One B-rep face of a CAD part: STEP entity #1113.
In plain terms, the planar face has unit normal (-1, 0, 0).
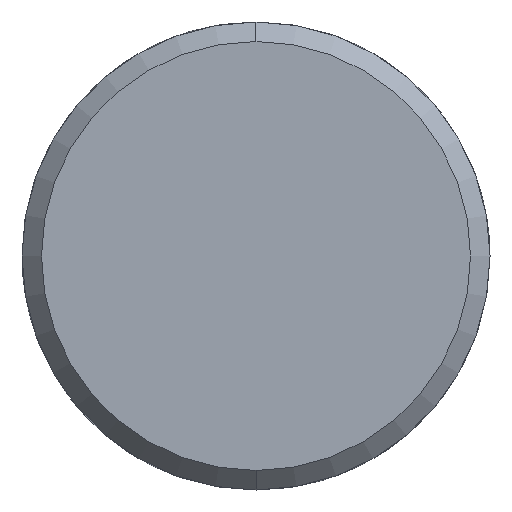
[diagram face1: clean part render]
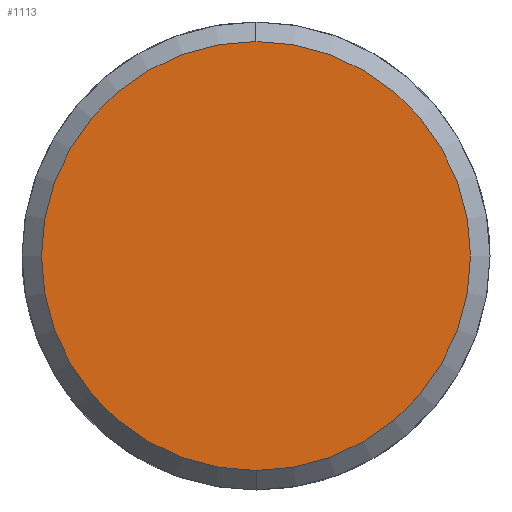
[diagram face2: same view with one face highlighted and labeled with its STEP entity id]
Its self-contained STEP definition (entity closure, numbers rounded to 3 decimals):
#1045=CARTESIAN_POINT('Vertex',(-5.,0.,-11.)) ;
#1048=CARTESIAN_POINT('Axis2P3D Location',(-5.,0.,0.)) ;
#1052=CARTESIAN_POINT('Vertex',(-5.,11.,0.)) ;
#1055=CARTESIAN_POINT('Axis2P3D Location',(-5.,0.,0.)) ;
#1059=CARTESIAN_POINT('Vertex',(-5.,0.,11.)) ;
#1081=CARTESIAN_POINT('Axis2P3D Location',(-5.,0.,0.)) ;
#1085=CARTESIAN_POINT('Vertex',(-5.,-11.,0.)) ;
#1088=CARTESIAN_POINT('Axis2P3D Location',(-5.,0.,0.)) ;
#1102=CARTESIAN_POINT('Axis2P3D Location',(-5.,0.,0.)) ;
#1049=DIRECTION('Axis2P3D Direction',(1.,0.,-0.)) ;
#1056=DIRECTION('Axis2P3D Direction',(1.,0.,-0.)) ;
#1082=DIRECTION('Axis2P3D Direction',(1.,0.,-0.)) ;
#1089=DIRECTION('Axis2P3D Direction',(1.,0.,-0.)) ;
#1103=DIRECTION('Axis2P3D Direction',(1.,0.,-0.)) ;
#1104=DIRECTION('Axis2P3D XDirection',(-0.,0.,-1.)) ;
#1050=AXIS2_PLACEMENT_3D('Circle Axis2P3D',#1048,#1049,$) ;
#1057=AXIS2_PLACEMENT_3D('Circle Axis2P3D',#1055,#1056,$) ;
#1083=AXIS2_PLACEMENT_3D('Circle Axis2P3D',#1081,#1082,$) ;
#1090=AXIS2_PLACEMENT_3D('Circle Axis2P3D',#1088,#1089,$) ;
#1105=AXIS2_PLACEMENT_3D('Plane Axis2P3D',#1102,#1103,#1104) ;
#1108=ORIENTED_EDGE('',*,*,#1054,.F.) ;
#1109=ORIENTED_EDGE('',*,*,#1092,.F.) ;
#1110=ORIENTED_EDGE('',*,*,#1087,.F.) ;
#1111=ORIENTED_EDGE('',*,*,#1061,.F.) ;
#1113=ADVANCED_FACE('351-14X46X70',(#1112),#1106,.F.) ;
#1051=CIRCLE('generated circle',#1050,11.) ;
#1058=CIRCLE('generated circle',#1057,11.) ;
#1084=CIRCLE('generated circle',#1083,11.) ;
#1091=CIRCLE('generated circle',#1090,11.) ;
#1054=EDGE_CURVE('',#1046,#1053,#1051,.T.) ;
#1061=EDGE_CURVE('',#1053,#1060,#1058,.T.) ;
#1087=EDGE_CURVE('',#1060,#1086,#1084,.T.) ;
#1092=EDGE_CURVE('',#1086,#1046,#1091,.T.) ;
#1107=EDGE_LOOP('',(#1108,#1109,#1110,#1111)) ;
#1112=FACE_OUTER_BOUND('',#1107,.T.) ;
#1106=PLANE('Plane',#1105) ;
#1046=VERTEX_POINT('',#1045) ;
#1053=VERTEX_POINT('',#1052) ;
#1060=VERTEX_POINT('',#1059) ;
#1086=VERTEX_POINT('',#1085) ;
